VERSION 5.8 ;
BUSBITCHARS "[]" ;
DIVIDERCHAR "/" ;

# Macros-only LEF, layered on the tech that sequnmap_basic.lef creates.

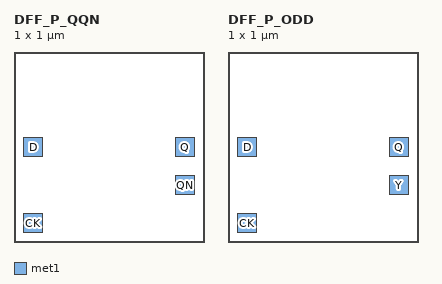
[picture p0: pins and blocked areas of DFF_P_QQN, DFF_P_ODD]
MACRO DFF_P_QQN
  CLASS CORE ; ORIGIN 0 0 ; SIZE 1.0 BY 1.0 ; SITE core ;
  PIN D DIRECTION INPUT ; USE SIGNAL ; PORT LAYER met1 ; RECT 0.05 0.45 0.15 0.55 ; END END D
  PIN CK DIRECTION INPUT ; USE CLOCK ; PORT LAYER met1 ; RECT 0.05 0.05 0.15 0.15 ; END END CK
  PIN Q DIRECTION OUTPUT ; USE SIGNAL ; PORT LAYER met1 ; RECT 0.85 0.45 0.95 0.55 ; END END Q
  PIN QN DIRECTION OUTPUT ; USE SIGNAL ; PORT LAYER met1 ; RECT 0.85 0.25 0.95 0.35 ; END END QN
END DFF_P_QQN

MACRO DFF_P_ODD
  CLASS CORE ; ORIGIN 0 0 ; SIZE 1.0 BY 1.0 ; SITE core ;
  PIN D DIRECTION INPUT ; USE SIGNAL ; PORT LAYER met1 ; RECT 0.05 0.45 0.15 0.55 ; END END D
  PIN CK DIRECTION INPUT ; USE CLOCK ; PORT LAYER met1 ; RECT 0.05 0.05 0.15 0.15 ; END END CK
  PIN Q DIRECTION OUTPUT ; USE SIGNAL ; PORT LAYER met1 ; RECT 0.85 0.45 0.95 0.55 ; END END Q
  PIN Y DIRECTION OUTPUT ; USE SIGNAL ; PORT LAYER met1 ; RECT 0.85 0.25 0.95 0.35 ; END END Y
END DFF_P_ODD

END LIBRARY
